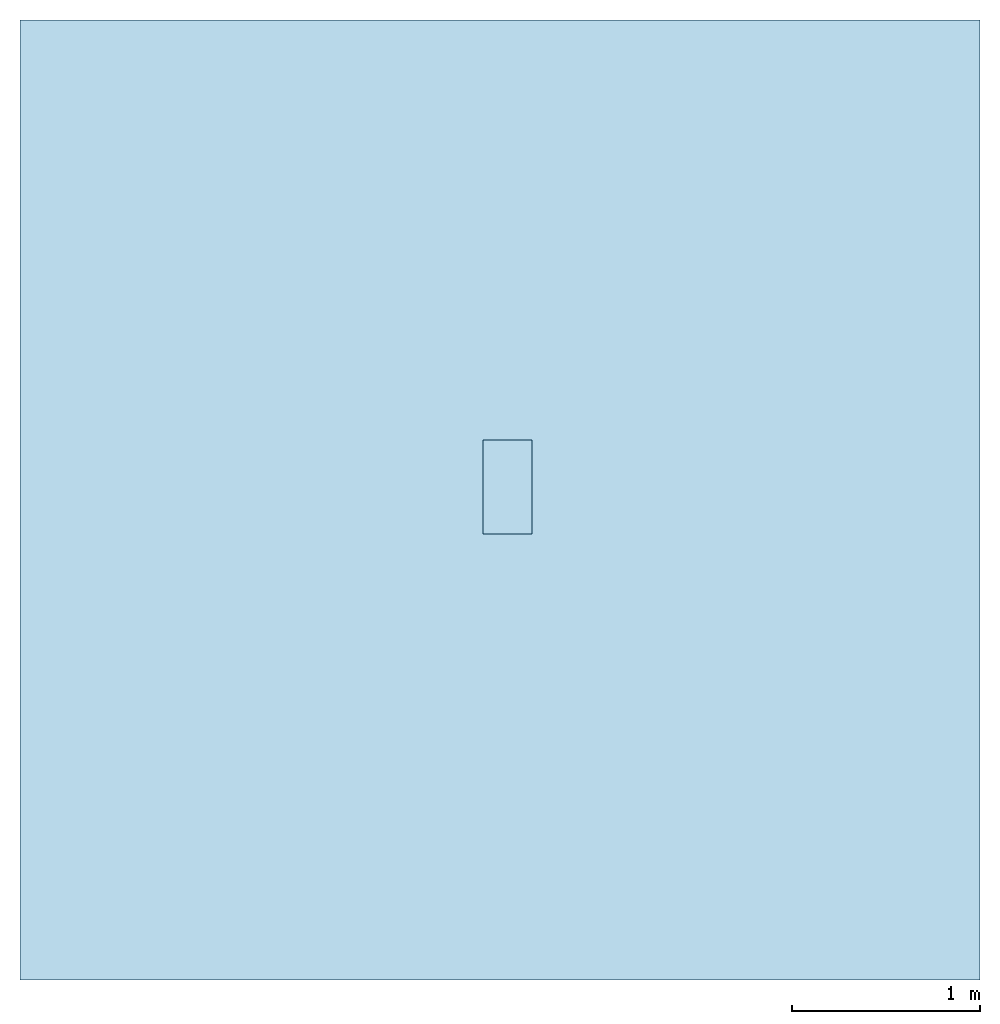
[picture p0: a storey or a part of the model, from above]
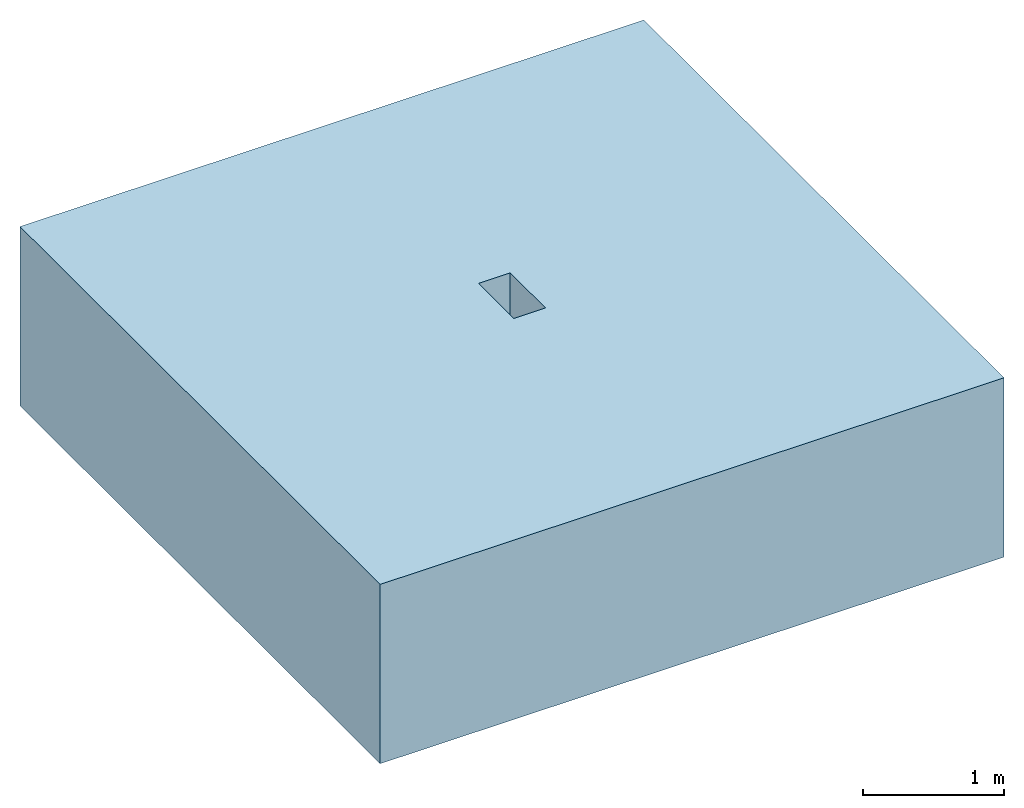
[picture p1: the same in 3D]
Properties of the parts of a building model (IFC2X3)

# File
Description: ViewDefinition [CoordinationView]
File name: 33301 - PD200 F 30.1 Channel 500mm LG.ifc
Time: 2013-10-11T12:58:01
Written by: Autodesk Revit 2013
Made in: 20120221_2030(x64)

# IfcProject, Project Number
LongName: Project Name; Phase: Project Status

# IfcSite, Default
RefLatitude: 42, 21, 30, 344238; RefLongitude: -71, -3, -35, -194702; RefElevation: 0 mm

# IfcBuilding
Pset_BuildingCommon - NumberOfStoreys: 2
Other - Project Issue Date: Issue Date; Project Number: Project Number; Project Status: Project Status; Project Name: Project Name; Client Name: Owner; Project Address: Enter address here

# IfcBuildingStorey (2)
Constraints - Elevation Base: 0
Graphics - Symbol: M_Level Head - Circle: M_Level Head - Circle; Symbol at End 2 Default: yes; Symbol at End 1 Default: no; Line Pattern: Center; Line Weight: 1; Color: 0
Identity Data - Structural: no; Building Story: yes
Dimensions - Computation Height: 0 mm
Name | LongName = Name | Elevation (mm) = Constraints, Elevation (mm)
B.O. Footing | B.O. Footing | -4600
T.O. Footing | T.O. Footing | -4300

# IfcBuildingElementProxy: 33301 - PD200 F 30.1 Channel 500mm LG, Civil-Drainage-Channel-ACO-RoadDrain 200:33301 - PD200 F 30.1 Channel 500mm LG:33301 - PD200 F 30.1 Channel 500mm LG:309971
In: B.O. Footing
Material: Acetal Resin, Black
Data - Connection Pipe O.D: N/A; Load Class: A 15 - F 900; Product Weight: 58.3 Kg; ACO Hydraulic Design Software: http://www.acodesign.co.uk; Installation - Concrete Grade: Refer to brochure; Invert Depth: 470mm; Product Standard: BS EN 1433:2002, CE marked, Kitemarked; Hydraulic Performance: http://www.aco.co.uk/download.php?id=256; Channel C.S.A: 0.061m²; Concrete Surround Volume - Load Class F 900 - Concrete Pavement: 0.33m³/m; Product Dimensions: 500mm x 260mm x 500mm (LxWxH)
Other - CreatedBy: www.aco.co.uk; Revision: 1
Construction - Closing End Cap: no; Access unit: no; Channel 260mm Wide: yes; Inlet Outlet end cap: no
Dimensions - Volume: 31451675 mm3; Custom Void Length: 0 mm; Straight Void Length: 500 mm; Length: 500 mm; Void Depth: -500 mm; Invert Depth.: 370 mm; Total Depth: 500 mm; I/O End Cap Void: 3010 mm; Pipe Depth: 5750 mm; Straight Void Start: 0 mm
Phasing - Phase Created: Phase 1
Constraints - Moves With Nearby Elements: no; Level: Level: T.O. Footing
Pset_BuildingElementProxyCommon - Reference: 33301 - PD200 F 30.1 Channel 500mm LG
General - TagNumber: 0.000000; SerialNumber: 0.000000
Identity Data - Maintenance guidelines: http://www.aco.co.uk/download.php?id=256; Cost: 0; Type Comments: ACO RoadDrain 100 PD200F 30.1 Constant Depth Channel 500mm Long; Product Page URL: http://www.aco.co.uk/product_detail.php?id=21; Model Description: Monolithic Channel drainage system; Assembly Description: Rain Water Drainage; Fax: +44 (0)1462 815895; Assembly Code: D2040; OmniClass Number: 23.70.50.24; Manufacturer: ACO Technologies plc - ACO Water Management Division; Address: ACO Business Park, Hitchin Road, Shefford, Bedfordshire, United Kingdom SG17 5TE; e-mail Technical: technical@aco.co.uk; Product brochure: http://www.aco.co.uk/download.php?id=256; e-mail Sales: customersupport@aco.co.uk; Installation guidelines: http://www.aco.co.uk/download.php?id=256; Price: POA - contact ACO; Watermarked With: BIM Manager Premium Suite; URL: www.aco.co.uk; Watermark 1: This file is the property of ACO Technologies PLC; OmniClass Title: Rainwater Removal; Telephone: +44 (0)1462 816666; Model: ACO RoadDrain 200 PD200F; Product Code: 33301; Watermark 2: This file is water marked and users are prohibited to reproduce, adapt, distribute this information; Watermarked By: www.aco.co.uk
Materials and Finishes - End Cap Colour: N/A; Connection Pipe Material: N/A; End Cap Material: N/A; Grating Material: N/A; Access Cover/Frame Finish: N/A; Grating Colour: N/A; Grating Finish: N/A; Access Cover/Frame Colour: N/A; Connection Pipe Colour: N/A; Access Cover/Frame Material: N/A; Channel Colour: Black; Channel Material: Vienite® Synthetic Resin Concrete
Green Building Properties - Channel Recycled Material Content: 20% minimum; End Cap Recyclable: N/A; Access Cover/Frame Recyclable: N/A; Access Cover/Frame Recycled Material Content: N/A; Channel Recyclable: Fully recyclable; End Cap Recycled Material Content: N/A

# IfcOpeningElement: Recess (2)
In: T.O. Footing
Phasing - Phase Created: Phase 1
Dimensions - Perimeter: 20400 mm; Thickness: 1550 mm; Area: 26010000 mm2; Volume: 40250500000 mm3
Constraints - Room Bounding: yes; Level: Level: T.O. Footing; Related to Mass: no; Height Offset From Level: 0 mm
Structural - Enable Analytical Model: no; Structural: no
Graphics - Coarse Scale Fill Color: 0
Construction - Default Thickness: 1550 mm; Function: 0
Analytical Properties - Roughness: 1; Thermal Resistance (R): 1.79211; Thermal mass: 2039700; Absorptance: 0.1; Heat Transfer Coefficient (U): 0.558
Materials and Finishes - Structural Material: Grass

# IfcSlab: Floor:Generic Floor - 400mm, Floor:Generic Floor - 400mm:136436
In: T.O. Footing
PredefinedType: FLOOR; Material: Grass 50 mm, Earth 1500 mm
Phasing - Phase Created: Phase 1
Dimensions - Perimeter: 20400 mm; Thickness: 1550 mm; Area: 26010000 mm2; Volume: 40250500000 mm3
Constraints - Room Bounding: yes; Level: Level: T.O. Footing; Related to Mass: no; Height Offset From Level: 0 mm
Structural - Enable Analytical Model: no; Structural: no
Pset_SlabCommon - Reference: Generic Floor - 400mm; IsExternal: no; LoadBearing: yes
Graphics - Coarse Scale Fill Color: 0
Construction - Default Thickness: 1550 mm; Function: 0
Analytical Properties - Roughness: 1; Thermal Resistance (R): 1.79211; Thermal mass: 2039700; Absorptance: 0.1; Heat Transfer Coefficient (U): 0.558
Materials and Finishes - Structural Material: Grass
